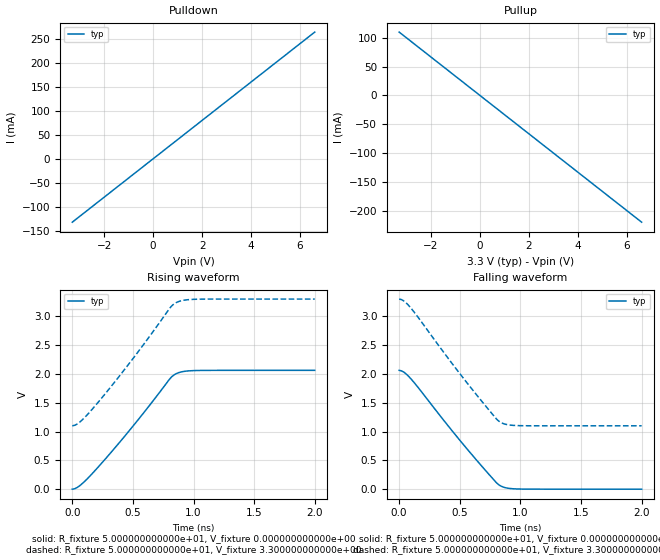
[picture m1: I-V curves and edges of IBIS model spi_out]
[IBIS Ver] 3.2
[File Name] demo_mcu.ibs
[File Rev] 1.0
[Component] DEMO_MCU
Manufacturer verax demo (synthetic, linear tables)
[Package]
R_pkg 0.2 NA NA
L_pkg 2nH NA NA
C_pkg 0.5pF NA NA
[Pin] signal_name model_name R_pin L_pin C_pin
1 SCK  spi_out
2 MOSI spi_out
3 VCC  POWER
4 GND  GND
| Models and submodels in the file (1): spi_out (Output)
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[Model] spi_out
Model_type Output
C_comp 3.000000000000e-12 NA NA
Vinl = 0.8
Vinh = 2.0
Vmeas = 1.65
Rref = 50
Vref = 0
Cref = 0
[Voltage Range] 3.300000000000e+00 NA NA
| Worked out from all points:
|   slope of the pulldown table from 0 to 0.495 V, typ, clamps not added: 25 ohm
|   slope of the pullup table from 0 to 0.495 V, typ, clamps not added: 30 ohm
|   rising waveform, R_fixture 5.000000000000e+01, V_fixture 0.000000000000e+00: 20-80 % time 483ps typ, NA min, NA max; typ from 0 V to 2.06 V
|   rising waveform, R_fixture 5.000000000000e+01, V_fixture 3.300000000000e+00: 20-80 % time 483ps typ, NA min, NA max; typ from 1.1 V to 3.3 V
|   falling waveform, R_fixture 5.000000000000e+01, V_fixture 0.000000000000e+00: 20-80 % time 477ps typ, NA min, NA max; typ from 2.06 V to 0 V
|   falling waveform, R_fixture 5.000000000000e+01, V_fixture 3.300000000000e+00: 20-80 % time 477ps typ, NA min, NA max; typ from 3.3 V to 1.1 V
[Pulldown]
-3.3V     -132mA     NA         NA
-1.65V    -66mA      NA         NA
0V        0A         NA         NA
1.65V     66mA       NA         NA
3.3V      132mA      NA         NA
4.95V     198mA      NA         NA
6.6V      264mA      NA         NA
[Pullup]
-3.3V     110mA      NA         NA
-1.65V    55mA       NA         NA
0V        0A         NA         NA
1.65V     -55mA      NA         NA
3.3V      -110mA     NA         NA
4.95V     -165mA     NA         NA
6.6V      -220mA     NA         NA
[Ramp]
dV/dt_r 1.980000000000e+00/4.800000000000e-10 NA NA
dV/dt_f 1.980000000000e+00/4.800000000000e-10 NA NA
R_load = 50
[Rising Waveform]
R_fixture = 5.000000000000e+01
V_fixture = 0.000000000000e+00
0s        0V         NA         NA
40ps      28.6mV     NA         NA
80ps      92.21mV    NA         NA
200ps     351.6mV    NA         NA
500ps     1.092V     NA         NA
800ps     1.903V     NA         NA
860ps     2.008V     NA         NA
920ps     2.044V     NA         NA
1.02ns    2.059V     NA         NA
2ns       2.062V     NA         NA
[Rising Waveform]
R_fixture = 5.000000000000e+01
V_fixture = 3.300000000000e+00
0s        1.1V       NA         NA
40ps      1.131V     NA         NA
80ps      1.198V     NA         NA
200ps     1.475V     NA         NA
500ps     2.265V     NA         NA
800ps     3.13V      NA         NA
860ps     3.242V     NA         NA
920ps     3.28V      NA         NA
1.02ns    3.297V     NA         NA
2ns       3.3V       NA         NA
[Falling Waveform]
R_fixture = 5.000000000000e+01
V_fixture = 0.000000000000e+00
0s        2.062V     NA         NA
40ps      2.03V      NA         NA
100ps     1.909V     NA         NA
400ps     1.11V      NA         NA
560ps     698.7mV    NA         NA
800ps     117.1mV    NA         NA
840ps     52.6mV     NA         NA
900ps     15.84mV    NA         NA
1ns       2.144mV    NA         NA
2ns       4.419pV    NA         NA
[Falling Waveform]
R_fixture = 5.000000000000e+01
V_fixture = 3.300000000000e+00
0s        3.3V       NA         NA
40ps      3.265V     NA         NA
100ps     3.136V     NA         NA
400ps     2.284V     NA         NA
560ps     1.845V     NA         NA
800ps     1.225V     NA         NA
840ps     1.156V     NA         NA
900ps     1.117V     NA         NA
1ns       1.102V     NA         NA
2ns       1.1V       NA         NA
[End Model]
